VERSION 5.7 ;
  NOWIREEXTENSIONATPIN ON ;
  DIVIDERCHAR "/" ;
  BUSBITCHARS "[]" ;
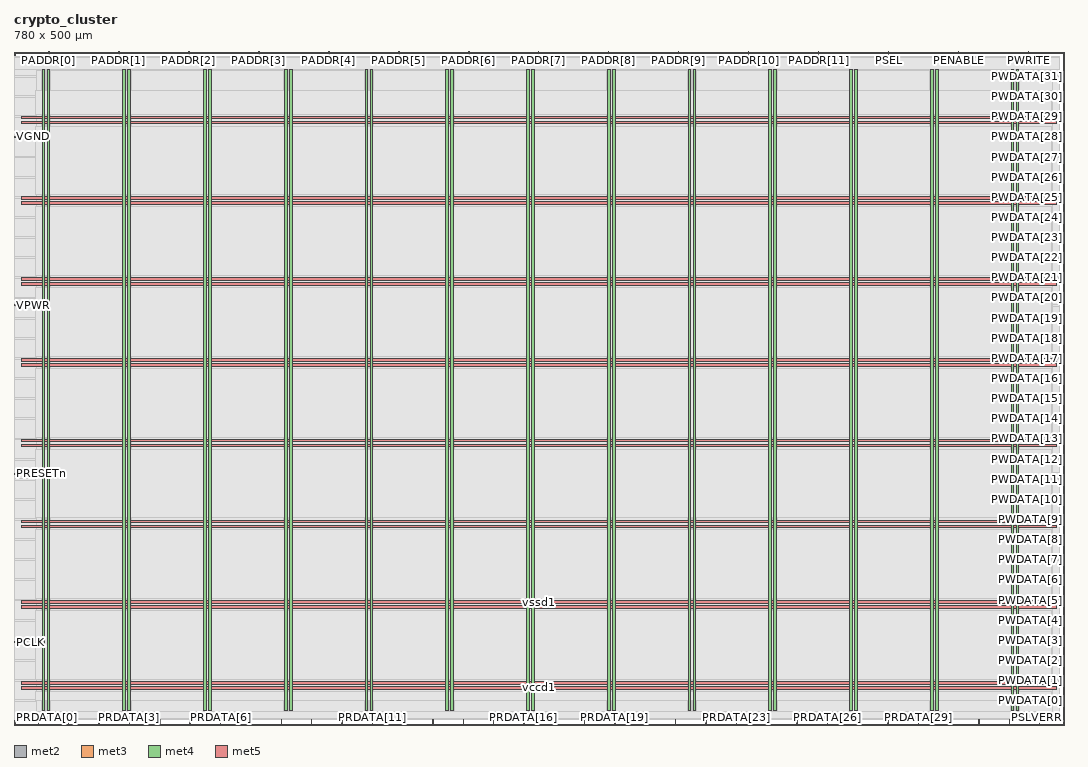
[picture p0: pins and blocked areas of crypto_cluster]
MACRO crypto_cluster
  CLASS BLOCK ;
  FOREIGN crypto_cluster ;
  ORIGIN 0.000 0.000 ;
  SIZE 780.000 BY 500.000 ;
  PIN PADDR[0]
    DIRECTION INPUT ;
    USE SIGNAL ;
    PORT
      LAYER met2 ;
        RECT 25.850 496.000 26.130 500.000 ;
    END
  END PADDR[0]
  PIN PADDR[10]
    DIRECTION INPUT ;
    USE SIGNAL ;
    PORT
      LAYER met2 ;
        RECT 545.650 496.000 545.930 500.000 ;
    END
  END PADDR[10]
  PIN PADDR[11]
    DIRECTION INPUT ;
    USE SIGNAL ;
    PORT
      LAYER met2 ;
        RECT 597.630 496.000 597.910 500.000 ;
    END
  END PADDR[11]
  PIN PADDR[1]
    DIRECTION INPUT ;
    USE SIGNAL ;
    PORT
      LAYER met2 ;
        RECT 77.830 496.000 78.110 500.000 ;
    END
  END PADDR[1]
  PIN PADDR[2]
    DIRECTION INPUT ;
    USE SIGNAL ;
    ANTENNAGATEAREA 0.247500 ;
    PORT
      LAYER met2 ;
        RECT 129.810 496.000 130.090 500.000 ;
    END
  END PADDR[2]
  PIN PADDR[3]
    DIRECTION INPUT ;
    USE SIGNAL ;
    ANTENNAGATEAREA 0.213000 ;
    PORT
      LAYER met2 ;
        RECT 181.790 496.000 182.070 500.000 ;
    END
  END PADDR[3]
  PIN PADDR[4]
    DIRECTION INPUT ;
    USE SIGNAL ;
    ANTENNAGATEAREA 0.213000 ;
    PORT
      LAYER met2 ;
        RECT 233.770 496.000 234.050 500.000 ;
    END
  END PADDR[4]
  PIN PADDR[5]
    DIRECTION INPUT ;
    USE SIGNAL ;
    ANTENNAGATEAREA 0.213000 ;
    PORT
      LAYER met2 ;
        RECT 285.750 496.000 286.030 500.000 ;
    END
  END PADDR[5]
  PIN PADDR[6]
    DIRECTION INPUT ;
    USE SIGNAL ;
    ANTENNAGATEAREA 0.196500 ;
    PORT
      LAYER met2 ;
        RECT 337.730 496.000 338.010 500.000 ;
    END
  END PADDR[6]
  PIN PADDR[7]
    DIRECTION INPUT ;
    USE SIGNAL ;
    ANTENNAGATEAREA 0.196500 ;
    PORT
      LAYER met2 ;
        RECT 389.710 496.000 389.990 500.000 ;
    END
  END PADDR[7]
  PIN PADDR[8]
    DIRECTION INPUT ;
    USE SIGNAL ;
    ANTENNAGATEAREA 0.126000 ;
    PORT
      LAYER met2 ;
        RECT 441.690 496.000 441.970 500.000 ;
    END
  END PADDR[8]
  PIN PADDR[9]
    DIRECTION INPUT ;
    USE SIGNAL ;
    ANTENNAGATEAREA 0.213000 ;
    PORT
      LAYER met2 ;
        RECT 493.670 496.000 493.950 500.000 ;
    END
  END PADDR[9]
  PIN PCLK
    DIRECTION INPUT ;
    USE SIGNAL ;
    ANTENNAGATEAREA 1.286700 ;
    ANTENNADIFFAREA 0.434700 ;
    PORT
      LAYER met3 ;
        RECT 0.000 61.240 4.000 61.840 ;
    END
  END PCLK
  PIN PENABLE
    DIRECTION INPUT ;
    USE SIGNAL ;
    ANTENNAGATEAREA 0.196500 ;
    PORT
      LAYER met2 ;
        RECT 701.590 496.000 701.870 500.000 ;
    END
  END PENABLE
  PIN PRDATA[0]
    DIRECTION OUTPUT ;
    USE SIGNAL ;
    ANTENNADIFFAREA 0.445500 ;
    PORT
      LAYER met2 ;
        RECT 18.030 0.000 18.310 4.000 ;
    END
  END PRDATA[0]
  PIN PRDATA[10]
    DIRECTION OUTPUT ;
    USE SIGNAL ;
    ANTENNADIFFAREA 0.445500 ;
    PORT
      LAYER met2 ;
        RECT 243.430 0.000 243.710 4.000 ;
    END
  END PRDATA[10]
  PIN PRDATA[11]
    DIRECTION OUTPUT ;
    USE SIGNAL ;
    ANTENNADIFFAREA 0.445500 ;
    PORT
      LAYER met2 ;
        RECT 265.970 0.000 266.250 4.000 ;
    END
  END PRDATA[11]
  PIN PRDATA[12]
    DIRECTION OUTPUT ;
    USE SIGNAL ;
    ANTENNADIFFAREA 0.445500 ;
    PORT
      LAYER met2 ;
        RECT 288.510 0.000 288.790 4.000 ;
    END
  END PRDATA[12]
  PIN PRDATA[13]
    DIRECTION OUTPUT ;
    USE SIGNAL ;
    ANTENNADIFFAREA 0.445500 ;
    PORT
      LAYER met2 ;
        RECT 311.050 0.000 311.330 4.000 ;
    END
  END PRDATA[13]
  PIN PRDATA[14]
    DIRECTION OUTPUT ;
    USE SIGNAL ;
    ANTENNADIFFAREA 0.445500 ;
    PORT
      LAYER met2 ;
        RECT 333.590 0.000 333.870 4.000 ;
    END
  END PRDATA[14]
  PIN PRDATA[15]
    DIRECTION OUTPUT ;
    USE SIGNAL ;
    ANTENNADIFFAREA 0.445500 ;
    PORT
      LAYER met2 ;
        RECT 356.130 0.000 356.410 4.000 ;
    END
  END PRDATA[15]
  PIN PRDATA[16]
    DIRECTION OUTPUT ;
    USE SIGNAL ;
    ANTENNADIFFAREA 0.445500 ;
    PORT
      LAYER met2 ;
        RECT 378.670 0.000 378.950 4.000 ;
    END
  END PRDATA[16]
  PIN PRDATA[17]
    DIRECTION OUTPUT ;
    USE SIGNAL ;
    ANTENNADIFFAREA 0.445500 ;
    PORT
      LAYER met2 ;
        RECT 401.210 0.000 401.490 4.000 ;
    END
  END PRDATA[17]
  PIN PRDATA[18]
    DIRECTION OUTPUT ;
    USE SIGNAL ;
    ANTENNADIFFAREA 0.445500 ;
    PORT
      LAYER met2 ;
        RECT 423.750 0.000 424.030 4.000 ;
    END
  END PRDATA[18]
  PIN PRDATA[19]
    DIRECTION OUTPUT ;
    USE SIGNAL ;
    ANTENNADIFFAREA 0.445500 ;
    PORT
      LAYER met2 ;
        RECT 446.290 0.000 446.570 4.000 ;
    END
  END PRDATA[19]
  PIN PRDATA[1]
    DIRECTION OUTPUT ;
    USE SIGNAL ;
    ANTENNADIFFAREA 0.445500 ;
    PORT
      LAYER met2 ;
        RECT 40.570 0.000 40.850 4.000 ;
    END
  END PRDATA[1]
  PIN PRDATA[20]
    DIRECTION OUTPUT ;
    USE SIGNAL ;
    ANTENNADIFFAREA 0.445500 ;
    PORT
      LAYER met2 ;
        RECT 468.830 0.000 469.110 4.000 ;
    END
  END PRDATA[20]
  PIN PRDATA[21]
    DIRECTION OUTPUT ;
    USE SIGNAL ;
    ANTENNADIFFAREA 0.445500 ;
    PORT
      LAYER met2 ;
        RECT 491.370 0.000 491.650 4.000 ;
    END
  END PRDATA[21]
  PIN PRDATA[22]
    DIRECTION OUTPUT ;
    USE SIGNAL ;
    ANTENNADIFFAREA 0.445500 ;
    PORT
      LAYER met2 ;
        RECT 513.910 0.000 514.190 4.000 ;
    END
  END PRDATA[22]
  PIN PRDATA[23]
    DIRECTION OUTPUT ;
    USE SIGNAL ;
    ANTENNADIFFAREA 0.445500 ;
    PORT
      LAYER met2 ;
        RECT 536.450 0.000 536.730 4.000 ;
    END
  END PRDATA[23]
  PIN PRDATA[24]
    DIRECTION OUTPUT ;
    USE SIGNAL ;
    ANTENNADIFFAREA 0.445500 ;
    PORT
      LAYER met2 ;
        RECT 558.990 0.000 559.270 4.000 ;
    END
  END PRDATA[24]
  PIN PRDATA[25]
    DIRECTION OUTPUT ;
    USE SIGNAL ;
    ANTENNADIFFAREA 0.445500 ;
    PORT
      LAYER met2 ;
        RECT 581.530 0.000 581.810 4.000 ;
    END
  END PRDATA[25]
  PIN PRDATA[26]
    DIRECTION OUTPUT ;
    USE SIGNAL ;
    ANTENNADIFFAREA 0.445500 ;
    PORT
      LAYER met2 ;
        RECT 604.070 0.000 604.350 4.000 ;
    END
  END PRDATA[26]
  PIN PRDATA[27]
    DIRECTION OUTPUT ;
    USE SIGNAL ;
    ANTENNADIFFAREA 0.445500 ;
    PORT
      LAYER met2 ;
        RECT 626.610 0.000 626.890 4.000 ;
    END
  END PRDATA[27]
  PIN PRDATA[28]
    DIRECTION OUTPUT ;
    USE SIGNAL ;
    ANTENNADIFFAREA 0.445500 ;
    PORT
      LAYER met2 ;
        RECT 649.150 0.000 649.430 4.000 ;
    END
  END PRDATA[28]
  PIN PRDATA[29]
    DIRECTION OUTPUT ;
    USE SIGNAL ;
    ANTENNADIFFAREA 0.445500 ;
    PORT
      LAYER met2 ;
        RECT 671.690 0.000 671.970 4.000 ;
    END
  END PRDATA[29]
  PIN PRDATA[2]
    DIRECTION OUTPUT ;
    USE SIGNAL ;
    ANTENNADIFFAREA 0.445500 ;
    PORT
      LAYER met2 ;
        RECT 63.110 0.000 63.390 4.000 ;
    END
  END PRDATA[2]
  PIN PRDATA[30]
    DIRECTION OUTPUT ;
    USE SIGNAL ;
    ANTENNADIFFAREA 0.445500 ;
    PORT
      LAYER met2 ;
        RECT 694.230 0.000 694.510 4.000 ;
    END
  END PRDATA[30]
  PIN PRDATA[31]
    DIRECTION OUTPUT ;
    USE SIGNAL ;
    ANTENNADIFFAREA 0.445500 ;
    PORT
      LAYER met2 ;
        RECT 716.770 0.000 717.050 4.000 ;
    END
  END PRDATA[31]
  PIN PRDATA[3]
    DIRECTION OUTPUT ;
    USE SIGNAL ;
    ANTENNADIFFAREA 0.445500 ;
    PORT
      LAYER met2 ;
        RECT 85.650 0.000 85.930 4.000 ;
    END
  END PRDATA[3]
  PIN PRDATA[4]
    DIRECTION OUTPUT ;
    USE SIGNAL ;
    ANTENNADIFFAREA 0.445500 ;
    PORT
      LAYER met2 ;
        RECT 108.190 0.000 108.470 4.000 ;
    END
  END PRDATA[4]
  PIN PRDATA[5]
    DIRECTION OUTPUT ;
    USE SIGNAL ;
    ANTENNADIFFAREA 0.445500 ;
    PORT
      LAYER met2 ;
        RECT 130.730 0.000 131.010 4.000 ;
    END
  END PRDATA[5]
  PIN PRDATA[6]
    DIRECTION OUTPUT ;
    USE SIGNAL ;
    ANTENNADIFFAREA 0.445500 ;
    PORT
      LAYER met2 ;
        RECT 153.270 0.000 153.550 4.000 ;
    END
  END PRDATA[6]
  PIN PRDATA[7]
    DIRECTION OUTPUT ;
    USE SIGNAL ;
    ANTENNADIFFAREA 0.445500 ;
    PORT
      LAYER met2 ;
        RECT 175.810 0.000 176.090 4.000 ;
    END
  END PRDATA[7]
  PIN PRDATA[8]
    DIRECTION OUTPUT ;
    USE SIGNAL ;
    ANTENNADIFFAREA 0.445500 ;
    PORT
      LAYER met2 ;
        RECT 198.350 0.000 198.630 4.000 ;
    END
  END PRDATA[8]
  PIN PRDATA[9]
    DIRECTION OUTPUT ;
    USE SIGNAL ;
    ANTENNADIFFAREA 0.445500 ;
    PORT
      LAYER met2 ;
        RECT 220.890 0.000 221.170 4.000 ;
    END
  END PRDATA[9]
  PIN PREADY
    DIRECTION OUTPUT ;
    USE SIGNAL ;
    PORT
      LAYER met2 ;
        RECT 739.310 0.000 739.590 4.000 ;
    END
  END PREADY
  PIN PRESETn
    DIRECTION INPUT ;
    USE SIGNAL ;
    ANTENNAGATEAREA 0.196500 ;
    PORT
      LAYER met3 ;
        RECT 0.000 186.360 4.000 186.960 ;
    END
  END PRESETn
  PIN PSEL
    DIRECTION INPUT ;
    USE SIGNAL ;
    ANTENNAGATEAREA 0.196500 ;
    PORT
      LAYER met2 ;
        RECT 649.610 496.000 649.890 500.000 ;
    END
  END PSEL
  PIN PSLVERR
    DIRECTION OUTPUT ;
    USE SIGNAL ;
    PORT
      LAYER met2 ;
        RECT 761.850 0.000 762.130 4.000 ;
    END
  END PSLVERR
  PIN PWDATA[0]
    DIRECTION INPUT ;
    USE SIGNAL ;
    ANTENNAGATEAREA 0.247500 ;
    PORT
      LAYER met3 ;
        RECT 776.000 17.720 780.000 18.320 ;
    END
  END PWDATA[0]
  PIN PWDATA[10]
    DIRECTION INPUT ;
    USE SIGNAL ;
    ANTENNAGATEAREA 0.247500 ;
    PORT
      LAYER met3 ;
        RECT 776.000 167.320 780.000 167.920 ;
    END
  END PWDATA[10]
  PIN PWDATA[11]
    DIRECTION INPUT ;
    USE SIGNAL ;
    ANTENNAGATEAREA 0.213000 ;
    PORT
      LAYER met3 ;
        RECT 776.000 182.280 780.000 182.880 ;
    END
  END PWDATA[11]
  PIN PWDATA[12]
    DIRECTION INPUT ;
    USE SIGNAL ;
    ANTENNAGATEAREA 0.247500 ;
    PORT
      LAYER met3 ;
        RECT 776.000 197.240 780.000 197.840 ;
    END
  END PWDATA[12]
  PIN PWDATA[13]
    DIRECTION INPUT ;
    USE SIGNAL ;
    ANTENNAGATEAREA 0.247500 ;
    PORT
      LAYER met3 ;
        RECT 776.000 212.200 780.000 212.800 ;
    END
  END PWDATA[13]
  PIN PWDATA[14]
    DIRECTION INPUT ;
    USE SIGNAL ;
    ANTENNAGATEAREA 0.213000 ;
    PORT
      LAYER met3 ;
        RECT 776.000 227.160 780.000 227.760 ;
    END
  END PWDATA[14]
  PIN PWDATA[15]
    DIRECTION INPUT ;
    USE SIGNAL ;
    ANTENNAGATEAREA 0.159000 ;
    PORT
      LAYER met3 ;
        RECT 776.000 242.120 780.000 242.720 ;
    END
  END PWDATA[15]
  PIN PWDATA[16]
    DIRECTION INPUT ;
    USE SIGNAL ;
    ANTENNAGATEAREA 0.213000 ;
    PORT
      LAYER met3 ;
        RECT 776.000 257.080 780.000 257.680 ;
    END
  END PWDATA[16]
  PIN PWDATA[17]
    DIRECTION INPUT ;
    USE SIGNAL ;
    ANTENNAGATEAREA 0.213000 ;
    PORT
      LAYER met3 ;
        RECT 776.000 272.040 780.000 272.640 ;
    END
  END PWDATA[17]
  PIN PWDATA[18]
    DIRECTION INPUT ;
    USE SIGNAL ;
    ANTENNAGATEAREA 0.213000 ;
    PORT
      LAYER met3 ;
        RECT 776.000 287.000 780.000 287.600 ;
    END
  END PWDATA[18]
  PIN PWDATA[19]
    DIRECTION INPUT ;
    USE SIGNAL ;
    ANTENNAGATEAREA 0.213000 ;
    PORT
      LAYER met3 ;
        RECT 776.000 301.960 780.000 302.560 ;
    END
  END PWDATA[19]
  PIN PWDATA[1]
    DIRECTION INPUT ;
    USE SIGNAL ;
    ANTENNAGATEAREA 0.247500 ;
    PORT
      LAYER met3 ;
        RECT 776.000 32.680 780.000 33.280 ;
    END
  END PWDATA[1]
  PIN PWDATA[20]
    DIRECTION INPUT ;
    USE SIGNAL ;
    ANTENNAGATEAREA 0.213000 ;
    PORT
      LAYER met3 ;
        RECT 776.000 316.920 780.000 317.520 ;
    END
  END PWDATA[20]
  PIN PWDATA[21]
    DIRECTION INPUT ;
    USE SIGNAL ;
    ANTENNAGATEAREA 0.213000 ;
    PORT
      LAYER met3 ;
        RECT 776.000 331.880 780.000 332.480 ;
    END
  END PWDATA[21]
  PIN PWDATA[22]
    DIRECTION INPUT ;
    USE SIGNAL ;
    ANTENNAGATEAREA 0.213000 ;
    PORT
      LAYER met3 ;
        RECT 776.000 346.840 780.000 347.440 ;
    END
  END PWDATA[22]
  PIN PWDATA[23]
    DIRECTION INPUT ;
    USE SIGNAL ;
    ANTENNAGATEAREA 0.196500 ;
    PORT
      LAYER met3 ;
        RECT 776.000 361.800 780.000 362.400 ;
    END
  END PWDATA[23]
  PIN PWDATA[24]
    DIRECTION INPUT ;
    USE SIGNAL ;
    ANTENNAGATEAREA 0.126000 ;
    PORT
      LAYER met3 ;
        RECT 776.000 376.760 780.000 377.360 ;
    END
  END PWDATA[24]
  PIN PWDATA[25]
    DIRECTION INPUT ;
    USE SIGNAL ;
    ANTENNAGATEAREA 0.126000 ;
    PORT
      LAYER met3 ;
        RECT 776.000 391.720 780.000 392.320 ;
    END
  END PWDATA[25]
  PIN PWDATA[26]
    DIRECTION INPUT ;
    USE SIGNAL ;
    ANTENNAGATEAREA 0.196500 ;
    PORT
      LAYER met3 ;
        RECT 776.000 406.680 780.000 407.280 ;
    END
  END PWDATA[26]
  PIN PWDATA[27]
    DIRECTION INPUT ;
    USE SIGNAL ;
    ANTENNAGATEAREA 0.126000 ;
    PORT
      LAYER met3 ;
        RECT 776.000 421.640 780.000 422.240 ;
    END
  END PWDATA[27]
  PIN PWDATA[28]
    DIRECTION INPUT ;
    USE SIGNAL ;
    ANTENNAGATEAREA 0.196500 ;
    PORT
      LAYER met3 ;
        RECT 776.000 436.600 780.000 437.200 ;
    END
  END PWDATA[28]
  PIN PWDATA[29]
    DIRECTION INPUT ;
    USE SIGNAL ;
    ANTENNAGATEAREA 0.159000 ;
    PORT
      LAYER met3 ;
        RECT 776.000 451.560 780.000 452.160 ;
    END
  END PWDATA[29]
  PIN PWDATA[2]
    DIRECTION INPUT ;
    USE SIGNAL ;
    ANTENNAGATEAREA 0.247500 ;
    PORT
      LAYER met3 ;
        RECT 776.000 47.640 780.000 48.240 ;
    END
  END PWDATA[2]
  PIN PWDATA[30]
    DIRECTION INPUT ;
    USE SIGNAL ;
    ANTENNAGATEAREA 0.159000 ;
    PORT
      LAYER met3 ;
        RECT 776.000 466.520 780.000 467.120 ;
    END
  END PWDATA[30]
  PIN PWDATA[31]
    DIRECTION INPUT ;
    USE SIGNAL ;
    ANTENNAGATEAREA 0.247500 ;
    PORT
      LAYER met3 ;
        RECT 776.000 481.480 780.000 482.080 ;
    END
  END PWDATA[31]
  PIN PWDATA[3]
    DIRECTION INPUT ;
    USE SIGNAL ;
    ANTENNAGATEAREA 0.247500 ;
    PORT
      LAYER met3 ;
        RECT 776.000 62.600 780.000 63.200 ;
    END
  END PWDATA[3]
  PIN PWDATA[4]
    DIRECTION INPUT ;
    USE SIGNAL ;
    ANTENNAGATEAREA 0.213000 ;
    PORT
      LAYER met3 ;
        RECT 776.000 77.560 780.000 78.160 ;
    END
  END PWDATA[4]
  PIN PWDATA[5]
    DIRECTION INPUT ;
    USE SIGNAL ;
    ANTENNAGATEAREA 0.213000 ;
    PORT
      LAYER met3 ;
        RECT 776.000 92.520 780.000 93.120 ;
    END
  END PWDATA[5]
  PIN PWDATA[6]
    DIRECTION INPUT ;
    USE SIGNAL ;
    ANTENNAGATEAREA 0.213000 ;
    PORT
      LAYER met3 ;
        RECT 776.000 107.480 780.000 108.080 ;
    END
  END PWDATA[6]
  PIN PWDATA[7]
    DIRECTION INPUT ;
    USE SIGNAL ;
    ANTENNAGATEAREA 0.247500 ;
    PORT
      LAYER met3 ;
        RECT 776.000 122.440 780.000 123.040 ;
    END
  END PWDATA[7]
  PIN PWDATA[8]
    DIRECTION INPUT ;
    USE SIGNAL ;
    ANTENNAGATEAREA 0.247500 ;
    PORT
      LAYER met3 ;
        RECT 776.000 137.400 780.000 138.000 ;
    END
  END PWDATA[8]
  PIN PWDATA[9]
    DIRECTION INPUT ;
    USE SIGNAL ;
    ANTENNAGATEAREA 0.247500 ;
    PORT
      LAYER met3 ;
        RECT 776.000 152.360 780.000 152.960 ;
    END
  END PWDATA[9]
  PIN PWRITE
    DIRECTION INPUT ;
    USE SIGNAL ;
    ANTENNAGATEAREA 0.196500 ;
    PORT
      LAYER met2 ;
        RECT 753.570 496.000 753.850 500.000 ;
    END
  END PWRITE
  PIN VGND
    DIRECTION INOUT ;
    USE SIGNAL ;
    PORT
      LAYER met3 ;
        RECT 0.000 436.600 4.000 437.200 ;
    END
  END VGND
  PIN VPWR
    DIRECTION INOUT ;
    USE SIGNAL ;
    PORT
      LAYER met3 ;
        RECT 0.000 311.480 4.000 312.080 ;
    END
  END VPWR
  PIN vccd1
    DIRECTION INOUT ;
    USE POWER ;
    PORT
      LAYER met4 ;
        RECT 20.840 10.640 22.840 487.120 ;
    END
    PORT
      LAYER met4 ;
        RECT 80.840 10.640 82.840 487.120 ;
    END
    PORT
      LAYER met4 ;
        RECT 140.840 10.640 142.840 487.120 ;
    END
    PORT
      LAYER met4 ;
        RECT 200.840 10.640 202.840 487.120 ;
    END
    PORT
      LAYER met4 ;
        RECT 260.840 10.640 262.840 487.120 ;
    END
    PORT
      LAYER met4 ;
        RECT 320.840 10.640 322.840 487.120 ;
    END
    PORT
      LAYER met4 ;
        RECT 380.840 10.640 382.840 487.120 ;
    END
    PORT
      LAYER met4 ;
        RECT 440.840 10.640 442.840 487.120 ;
    END
    PORT
      LAYER met4 ;
        RECT 500.840 10.640 502.840 487.120 ;
    END
    PORT
      LAYER met4 ;
        RECT 560.840 10.640 562.840 487.120 ;
    END
    PORT
      LAYER met4 ;
        RECT 620.840 10.640 622.840 487.120 ;
    END
    PORT
      LAYER met4 ;
        RECT 680.840 10.640 682.840 487.120 ;
    END
    PORT
      LAYER met4 ;
        RECT 740.840 10.640 742.840 487.120 ;
    END
    PORT
      LAYER met5 ;
        RECT 5.280 26.530 774.420 28.530 ;
    END
    PORT
      LAYER met5 ;
        RECT 5.280 86.530 774.420 88.530 ;
    END
    PORT
      LAYER met5 ;
        RECT 5.280 146.530 774.420 148.530 ;
    END
    PORT
      LAYER met5 ;
        RECT 5.280 206.530 774.420 208.530 ;
    END
    PORT
      LAYER met5 ;
        RECT 5.280 266.530 774.420 268.530 ;
    END
    PORT
      LAYER met5 ;
        RECT 5.280 326.530 774.420 328.530 ;
    END
    PORT
      LAYER met5 ;
        RECT 5.280 386.530 774.420 388.530 ;
    END
    PORT
      LAYER met5 ;
        RECT 5.280 446.530 774.420 448.530 ;
    END
  END vccd1
  PIN vssd1
    DIRECTION INOUT ;
    USE GROUND ;
    PORT
      LAYER met4 ;
        RECT 24.540 10.640 26.540 487.120 ;
    END
    PORT
      LAYER met4 ;
        RECT 84.540 10.640 86.540 487.120 ;
    END
    PORT
      LAYER met4 ;
        RECT 144.540 10.640 146.540 487.120 ;
    END
    PORT
      LAYER met4 ;
        RECT 204.540 10.640 206.540 487.120 ;
    END
    PORT
      LAYER met4 ;
        RECT 264.540 10.640 266.540 487.120 ;
    END
    PORT
      LAYER met4 ;
        RECT 324.540 10.640 326.540 487.120 ;
    END
    PORT
      LAYER met4 ;
        RECT 384.540 10.640 386.540 487.120 ;
    END
    PORT
      LAYER met4 ;
        RECT 444.540 10.640 446.540 487.120 ;
    END
    PORT
      LAYER met4 ;
        RECT 504.540 10.640 506.540 487.120 ;
    END
    PORT
      LAYER met4 ;
        RECT 564.540 10.640 566.540 487.120 ;
    END
    PORT
      LAYER met4 ;
        RECT 624.540 10.640 626.540 487.120 ;
    END
    PORT
      LAYER met4 ;
        RECT 684.540 10.640 686.540 487.120 ;
    END
    PORT
      LAYER met4 ;
        RECT 744.540 10.640 746.540 487.120 ;
    END
    PORT
      LAYER met5 ;
        RECT 5.280 30.230 774.420 32.230 ;
    END
    PORT
      LAYER met5 ;
        RECT 5.280 90.230 774.420 92.230 ;
    END
    PORT
      LAYER met5 ;
        RECT 5.280 150.230 774.420 152.230 ;
    END
    PORT
      LAYER met5 ;
        RECT 5.280 210.230 774.420 212.230 ;
    END
    PORT
      LAYER met5 ;
        RECT 5.280 270.230 774.420 272.230 ;
    END
    PORT
      LAYER met5 ;
        RECT 5.280 330.230 774.420 332.230 ;
    END
    PORT
      LAYER met5 ;
        RECT 5.280 390.230 774.420 392.230 ;
    END
    PORT
      LAYER met5 ;
        RECT 5.280 450.230 774.420 452.230 ;
    END
  END vssd1
  OBS
      LAYER nwell ;
        RECT 5.330 10.795 774.370 487.070 ;
      LAYER li1 ;
        RECT 5.520 10.795 774.180 486.965 ;
      LAYER met1 ;
        RECT 4.210 5.480 776.870 489.560 ;
      LAYER met2 ;
        RECT 0.550 495.720 25.570 496.810 ;
        RECT 26.410 495.720 77.550 496.810 ;
        RECT 78.390 495.720 129.530 496.810 ;
        RECT 130.370 495.720 181.510 496.810 ;
        RECT 182.350 495.720 233.490 496.810 ;
        RECT 234.330 495.720 285.470 496.810 ;
        RECT 286.310 495.720 337.450 496.810 ;
        RECT 338.290 495.720 389.430 496.810 ;
        RECT 390.270 495.720 441.410 496.810 ;
        RECT 442.250 495.720 493.390 496.810 ;
        RECT 494.230 495.720 545.370 496.810 ;
        RECT 546.210 495.720 597.350 496.810 ;
        RECT 598.190 495.720 649.330 496.810 ;
        RECT 650.170 495.720 701.310 496.810 ;
        RECT 702.150 495.720 753.290 496.810 ;
        RECT 754.130 495.720 776.850 496.810 ;
        RECT 0.550 4.280 776.850 495.720 ;
        RECT 0.550 4.000 17.750 4.280 ;
        RECT 18.590 4.000 40.290 4.280 ;
        RECT 41.130 4.000 62.830 4.280 ;
        RECT 63.670 4.000 85.370 4.280 ;
        RECT 86.210 4.000 107.910 4.280 ;
        RECT 108.750 4.000 130.450 4.280 ;
        RECT 131.290 4.000 152.990 4.280 ;
        RECT 153.830 4.000 175.530 4.280 ;
        RECT 176.370 4.000 198.070 4.280 ;
        RECT 198.910 4.000 220.610 4.280 ;
        RECT 221.450 4.000 243.150 4.280 ;
        RECT 243.990 4.000 265.690 4.280 ;
        RECT 266.530 4.000 288.230 4.280 ;
        RECT 289.070 4.000 310.770 4.280 ;
        RECT 311.610 4.000 333.310 4.280 ;
        RECT 334.150 4.000 355.850 4.280 ;
        RECT 356.690 4.000 378.390 4.280 ;
        RECT 379.230 4.000 400.930 4.280 ;
        RECT 401.770 4.000 423.470 4.280 ;
        RECT 424.310 4.000 446.010 4.280 ;
        RECT 446.850 4.000 468.550 4.280 ;
        RECT 469.390 4.000 491.090 4.280 ;
        RECT 491.930 4.000 513.630 4.280 ;
        RECT 514.470 4.000 536.170 4.280 ;
        RECT 537.010 4.000 558.710 4.280 ;
        RECT 559.550 4.000 581.250 4.280 ;
        RECT 582.090 4.000 603.790 4.280 ;
        RECT 604.630 4.000 626.330 4.280 ;
        RECT 627.170 4.000 648.870 4.280 ;
        RECT 649.710 4.000 671.410 4.280 ;
        RECT 672.250 4.000 693.950 4.280 ;
        RECT 694.790 4.000 716.490 4.280 ;
        RECT 717.330 4.000 739.030 4.280 ;
        RECT 739.870 4.000 761.570 4.280 ;
        RECT 762.410 4.000 776.850 4.280 ;
      LAYER met3 ;
        RECT 0.525 482.480 776.875 487.045 ;
        RECT 0.525 481.080 775.600 482.480 ;
        RECT 0.525 467.520 776.875 481.080 ;
        RECT 0.525 466.120 775.600 467.520 ;
        RECT 0.525 452.560 776.875 466.120 ;
        RECT 0.525 451.160 775.600 452.560 ;
        RECT 0.525 437.600 776.875 451.160 ;
        RECT 4.400 436.200 775.600 437.600 ;
        RECT 0.525 422.640 776.875 436.200 ;
        RECT 0.525 421.240 775.600 422.640 ;
        RECT 0.525 407.680 776.875 421.240 ;
        RECT 0.525 406.280 775.600 407.680 ;
        RECT 0.525 392.720 776.875 406.280 ;
        RECT 0.525 391.320 775.600 392.720 ;
        RECT 0.525 377.760 776.875 391.320 ;
        RECT 0.525 376.360 775.600 377.760 ;
        RECT 0.525 362.800 776.875 376.360 ;
        RECT 0.525 361.400 775.600 362.800 ;
        RECT 0.525 347.840 776.875 361.400 ;
        RECT 0.525 346.440 775.600 347.840 ;
        RECT 0.525 332.880 776.875 346.440 ;
        RECT 0.525 331.480 775.600 332.880 ;
        RECT 0.525 317.920 776.875 331.480 ;
        RECT 0.525 316.520 775.600 317.920 ;
        RECT 0.525 312.480 776.875 316.520 ;
        RECT 4.400 311.080 776.875 312.480 ;
        RECT 0.525 302.960 776.875 311.080 ;
        RECT 0.525 301.560 775.600 302.960 ;
        RECT 0.525 288.000 776.875 301.560 ;
        RECT 0.525 286.600 775.600 288.000 ;
        RECT 0.525 273.040 776.875 286.600 ;
        RECT 0.525 271.640 775.600 273.040 ;
        RECT 0.525 258.080 776.875 271.640 ;
        RECT 0.525 256.680 775.600 258.080 ;
        RECT 0.525 243.120 776.875 256.680 ;
        RECT 0.525 241.720 775.600 243.120 ;
        RECT 0.525 228.160 776.875 241.720 ;
        RECT 0.525 226.760 775.600 228.160 ;
        RECT 0.525 213.200 776.875 226.760 ;
        RECT 0.525 211.800 775.600 213.200 ;
        RECT 0.525 198.240 776.875 211.800 ;
        RECT 0.525 196.840 775.600 198.240 ;
        RECT 0.525 187.360 776.875 196.840 ;
        RECT 4.400 185.960 776.875 187.360 ;
        RECT 0.525 183.280 776.875 185.960 ;
        RECT 0.525 181.880 775.600 183.280 ;
        RECT 0.525 168.320 776.875 181.880 ;
        RECT 0.525 166.920 775.600 168.320 ;
        RECT 0.525 153.360 776.875 166.920 ;
        RECT 0.525 151.960 775.600 153.360 ;
        RECT 0.525 138.400 776.875 151.960 ;
        RECT 0.525 137.000 775.600 138.400 ;
        RECT 0.525 123.440 776.875 137.000 ;
        RECT 0.525 122.040 775.600 123.440 ;
        RECT 0.525 108.480 776.875 122.040 ;
        RECT 0.525 107.080 775.600 108.480 ;
        RECT 0.525 93.520 776.875 107.080 ;
        RECT 0.525 92.120 775.600 93.520 ;
        RECT 0.525 78.560 776.875 92.120 ;
        RECT 0.525 77.160 775.600 78.560 ;
        RECT 0.525 63.600 776.875 77.160 ;
        RECT 0.525 62.240 775.600 63.600 ;
        RECT 4.400 62.200 775.600 62.240 ;
        RECT 4.400 60.840 776.875 62.200 ;
        RECT 0.525 48.640 776.875 60.840 ;
        RECT 0.525 47.240 775.600 48.640 ;
        RECT 0.525 33.680 776.875 47.240 ;
        RECT 0.525 32.280 775.600 33.680 ;
        RECT 0.525 18.720 776.875 32.280 ;
        RECT 0.525 17.320 775.600 18.720 ;
        RECT 0.525 4.935 776.875 17.320 ;
      LAYER met4 ;
        RECT 16.430 10.240 20.440 486.025 ;
        RECT 23.240 10.240 24.140 486.025 ;
        RECT 26.940 10.240 80.440 486.025 ;
        RECT 83.240 10.240 84.140 486.025 ;
        RECT 86.940 10.240 140.440 486.025 ;
        RECT 143.240 10.240 144.140 486.025 ;
        RECT 146.940 10.240 200.440 486.025 ;
        RECT 203.240 10.240 204.140 486.025 ;
        RECT 206.940 10.240 260.440 486.025 ;
        RECT 263.240 10.240 264.140 486.025 ;
        RECT 266.940 10.240 320.440 486.025 ;
        RECT 323.240 10.240 324.140 486.025 ;
        RECT 326.940 10.240 380.440 486.025 ;
        RECT 383.240 10.240 384.140 486.025 ;
        RECT 386.940 10.240 440.440 486.025 ;
        RECT 443.240 10.240 444.140 486.025 ;
        RECT 446.940 10.240 500.440 486.025 ;
        RECT 503.240 10.240 504.140 486.025 ;
        RECT 506.940 10.240 560.440 486.025 ;
        RECT 563.240 10.240 564.140 486.025 ;
        RECT 566.940 10.240 620.440 486.025 ;
        RECT 623.240 10.240 624.140 486.025 ;
        RECT 626.940 10.240 680.440 486.025 ;
        RECT 683.240 10.240 684.140 486.025 ;
        RECT 686.940 10.240 740.440 486.025 ;
        RECT 743.240 10.240 744.140 486.025 ;
        RECT 746.940 10.240 771.585 486.025 ;
        RECT 16.430 4.935 771.585 10.240 ;
      LAYER met5 ;
        RECT 16.220 453.830 770.380 471.700 ;
        RECT 16.220 393.830 770.380 444.930 ;
        RECT 16.220 333.830 770.380 384.930 ;
        RECT 16.220 273.830 770.380 324.930 ;
        RECT 16.220 213.830 770.380 264.930 ;
        RECT 16.220 153.830 770.380 204.930 ;
        RECT 16.220 93.830 770.380 144.930 ;
        RECT 16.220 33.830 770.380 84.930 ;
        RECT 16.220 17.900 770.380 24.930 ;
  END
END crypto_cluster
END LIBRARY

